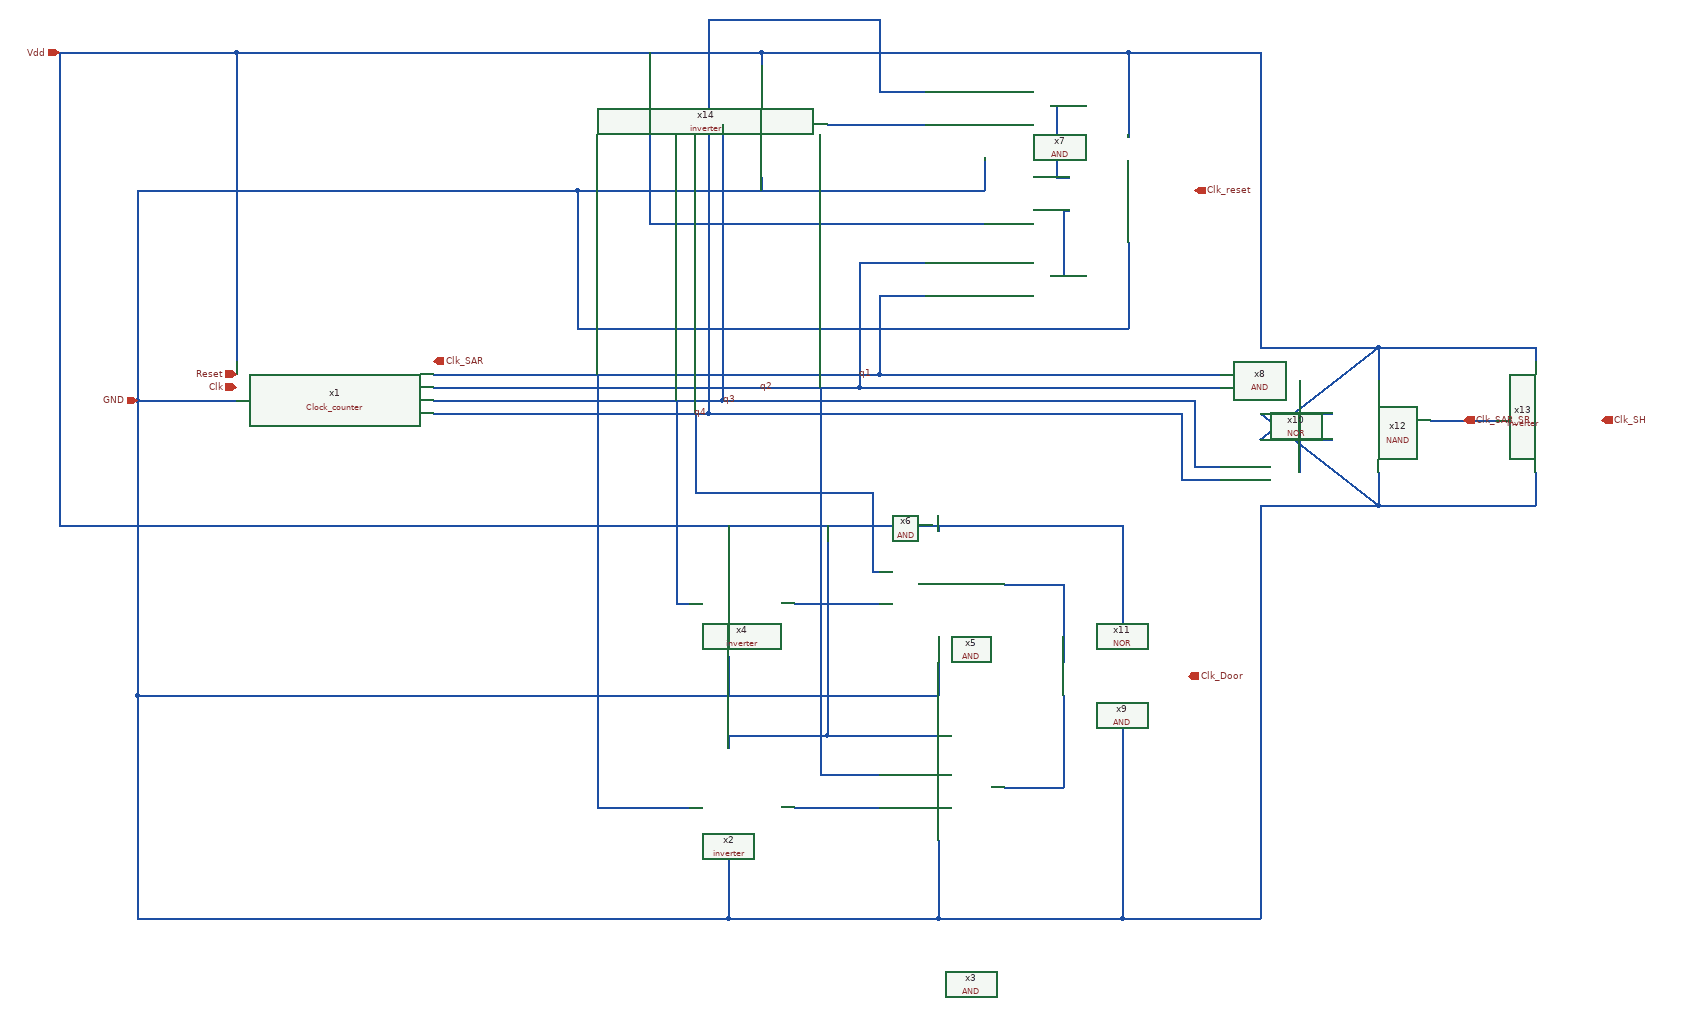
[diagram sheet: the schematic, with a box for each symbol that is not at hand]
v {xschem version=3.4.8RC file_version=1.3}
G {}
K {}
V {}
S {}
F {}
E {}
N 790 -180 810 -180 {lab=#net1}
N 810 -280 810 -180 {lab=#net1}
N 810 -280 820 -280 {lab=#net1}
N 790 -440 800 -440 {lab=#net2}
N 800 -440 800 -330 {lab=#net2}
N 800 -330 820 -330 {lab=#net2}
N 530 -460 600 -460 {lab=q4}
N 450 -410 600 -410 {lab=#net3}
N 690 -360 690 -310 {lab=GND}
N 220 -310 690 -310 {lab=GND}
N 350 -330 350 -310 {lab=GND}
N 220 -260 690 -260 {lab=Vdd}
N 70 -100 690 -100 {lab=GND}
N 70 -310 220 -310 {lab=GND}
N 530 -200 600 -200 {lab=q2}
N 530 -150 600 -150 {lab=q1}
N 350 -520 350 -510 {lab=Vdd}
N 350 -510 350 -500 {lab=Vdd}
N 690 -520 910 -520 {lab=Vdd}
N 910 -520 910 -390 {lab=Vdd}
N 690 -100 910 -100 {lab=GND}
N 910 -220 910 -100 {lab=GND}
N 910 -230 910 -220 {lab=GND}
N -150 -30 530 -30 {lab=q1}
N 530 -150 530 -30 {lab=q1}
N 500 -200 530 -200 {lab=q2}
N 500 -200 500 -10 {lab=q2}
N -150 -10 500 -10 {lab=q2}
N -150 10 290 10 {lab=q3}
N 290 -410 290 10 {lab=q3}
N 530 -570 530 -460 {lab=q4}
N 270 -570 530 -570 {lab=q4}
N 270 -570 270 30 {lab=q4}
N -150 30 270 30 {lab=q4}
N 350 -520 690 -520 {lab=Vdd}
N -200 -520 350 -520 {lab=Vdd}
N -180 -310 70 -310 {lab=GND}
N -190 -310 -180 -310 {lab=GND}
N 180 -260 220 -260 {lab=Vdd}
N 180 -520 180 -260 {lab=Vdd}
N 70 -310 70 -100 {lab=GND}
N -450 -520 -450 -50 {lab=Vdd}
N -450 -520 -200 -520 {lab=Vdd}
N -600 -310 -190 -310 {lab=GND}
N -600 -310 -600 10 {lab=GND}
N -600 10 -450 10 {lab=GND}
N 400 630 530 630 {lab=#net4}
N 440 580 530 580 {lab=q2}
N 100 -30 100 630 {lab=q1}
N 100 630 230 630 {lab=q1}
N 440 -10 440 580 {lab=q2}
N 400 320 530 320 {lab=#net5}
N 220 10 220 320 {lab=q3}
N 220 320 240 320 {lab=q3}
N 250 30 250 150 {lab=q4}
N 250 150 520 150 {lab=q4}
N 520 150 520 270 {lab=q4}
N 520 270 530 270 {lab=q4}
N -720 -520 -450 -520 {lab=Vdd}
N -720 -520 -720 200 {lab=Vdd}
N -720 200 620 200 {lab=Vdd}
N 620 200 620 210 {lab=Vdd}
N 300 200 300 230 {lab=Vdd}
N 450 520 620 520 {lab=Vdd}
N 450 200 450 520 {lab=Vdd}
N 300 520 450 520 {lab=Vdd}
N 300 520 300 540 {lab=Vdd}
N -600 10 -600 460 {lab=GND}
N -600 460 620 460 {lab=GND}
N 620 370 620 460 {lab=GND}
N 300 400 300 460 {lab=GND}
N 300 710 300 800 {lab=GND}
N 300 800 620 800 {lab=GND}
N 620 680 620 800 {lab=GND}
N -600 460 -600 800 {lab=GND}
N -600 800 300 800 {lab=GND}
N 230 630 240 630 {lab=q1}
N 720 600 810 600 {lab=#net6}
N 810 460 810 600 {lab=#net6}
N 810 290 810 410 {lab=#net7}
N 720 290 810 290 {lab=#net7}
N 900 210 900 350 {lab=Vdd}
N 900 200 900 210 {lab=Vdd}
N 610 200 900 200 {lab=Vdd}
N 900 510 900 800 {lab=GND}
N 620 800 900 800 {lab=GND}
N 530 -30 1050 -30 {lab=q1}
N 500 -10 1050 -10 {lab=q2}
N 290 10 1010 10 {lab=q3}
N 1010 10 1010 110 {lab=q3}
N 1010 110 1050 110 {lab=q3}
N 990 130 1050 130 {lab=q4}
N 990 40 990 130 {lab=q4}
N 270 30 990 30 {lab=q4}
N 990 30 990 40 {lab=q4}
N 1170 -20 1170 30 {lab=#net8}
N 1170 30 1220 30 {lab=#net8}
N 1170 70 1170 120 {lab=#net9}
N 1170 70 1220 70 {lab=#net9}
N 1110 170 1290 170 {lab=GND}
N 1290 120 1290 170 {lab=GND}
N 1110 -70 1290 -70 {lab=Vdd}
N 1290 -70 1290 -20 {lab=Vdd}
N 910 -520 1080 -520 {lab=Vdd}
N 1080 -520 1100 -520 {lab=Vdd}
N 1100 -520 1110 -520 {lab=Vdd}
N 1110 -520 1110 -80 {lab=Vdd}
N 1110 -80 1110 -70 {lab=Vdd}
N 900 800 1110 800 {lab=GND}
N 1110 170 1110 800 {lab=GND}
N 1110 30 1290 170 {lab=GND}
N 1110 70 1290 -70 {lab=Vdd}
N 1370 40 1470 40 {lab=Clk_SAR_SR}
N 1290 -70 1530 -70 {lab=Vdd}
N 1530 -70 1530 -50 {lab=Vdd}
N 1290 170 1530 170 {lab=GND}
N 1530 120 1530 170 {lab=GND}
C {/home/jetha/Projects/sky130/SAR_ADC/inverter/AND.sym} 740 -140 0 0 {name=x7}
C {/home/jetha/Projects/sky130/SAR_ADC/inverter/AND.sym} 740 120 0 0 {name=x6}
C {/home/jetha/Projects/sky130/SAR_ADC/inverter/AND.sym} 960 -10 0 0 {name=x8}
C {/home/jetha/Projects/sky130/SAR_ADC/inverter/inverter.sym} 310 -250 0 0 {name=x14}
C {lab_pin.sym} 370 -10 3 0 {name=p20 sig_type=std_logic lab=q2}
C {lab_pin.sym} 270 30 3 0 {name=p21 sig_type=std_logic lab=q4}
C {Clock_counter.sym} -300 -10 0 0 {name=x1}
C {lab_pin.sym} 290 10 2 0 {name=p4 sig_type=std_logic lab=q3}
C {lab_pin.sym} 520 -30 3 0 {name=p5 sig_type=std_logic lab=q1
spice_ignore=short}
C {/home/jetha/Projects/sky130/SAR_ADC/inverter/AND.sym} 670 900 0 0 {name=x3}
C {/home/jetha/Projects/sky130/SAR_ADC/inverter/inverter.sym} 260 790 0 0 {name=x2}
C {/home/jetha/Projects/sky130/SAR_ADC/inverter/inverter.sym} 260 480 0 0 {name=x4}
C {/home/jetha/Projects/sky130/SAR_ADC/inverter/AND.sym} 670 590 0 0 {name=x5}
C {/home/jetha/Projects/sky130/SAR_ADC/inverter/AND.sym} 950 730 0 0 {name=x9}
C {/home/jetha/Projects/sky130/SAR_ADC/inverter/NOR.sym} 1140 120 0 0 {name=x10}
C {/home/jetha/Projects/sky130/SAR_ADC/inverter/NOR.sym} 1140 260 0 0 {name=x11}
C {/home/jetha/Projects/sky130/SAR_ADC/inverter/NAND.sym} 1360 200 0 0 {name=x12}
C {/home/jetha/Projects/sky130/SAR_ADC/inverter/inverter.sym} 1490 200 0 0 {name=x13}
C {ipin.sym} -450 -10 0 0 {name=p11 lab=Clk}
C {ipin.sym} -450 -30 0 0 {name=p1 lab=Reset}
C {ipin.sym} -720 -520 0 0 {name=p3 lab=Vdd}
C {ipin.sym} -600 10 0 0 {name=p2 lab=GND}
C {opin.sym} 1010 -310 0 0 {name=p12 lab=Clk_reset}
C {opin.sym} 1630 40 0 0 {name=p6 lab=Clk_SH}
C {opin.sym} 1420 40 1 0 {name=p8 lab=Clk_SAR_SR}
C {opin.sym} 1000 430 0 0 {name=p7 lab=Clk_Door}
C {opin.sym} -150 -50 0 0 {name=p9 lab=Clk_SAR}
